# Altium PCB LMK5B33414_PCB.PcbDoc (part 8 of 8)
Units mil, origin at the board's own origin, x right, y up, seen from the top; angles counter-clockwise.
Board outline 7000 x 9161 mil, 8 copper layers (L1-Top Layer (GTL), L2-GND Plane (GP1), L3-Mid-Layer 2 (G1), L4-Mid-Layer 3 (G2), L5-Mid-Layer 4 (G3), L6-Mid-Layer 5 (G4), L7-Mid-Layer 6 (G5), L8-Bottom Layer (GBL)), stack 61.2 mil thick; 518 components, 286 nets, 1400 pads, 2231 vias.

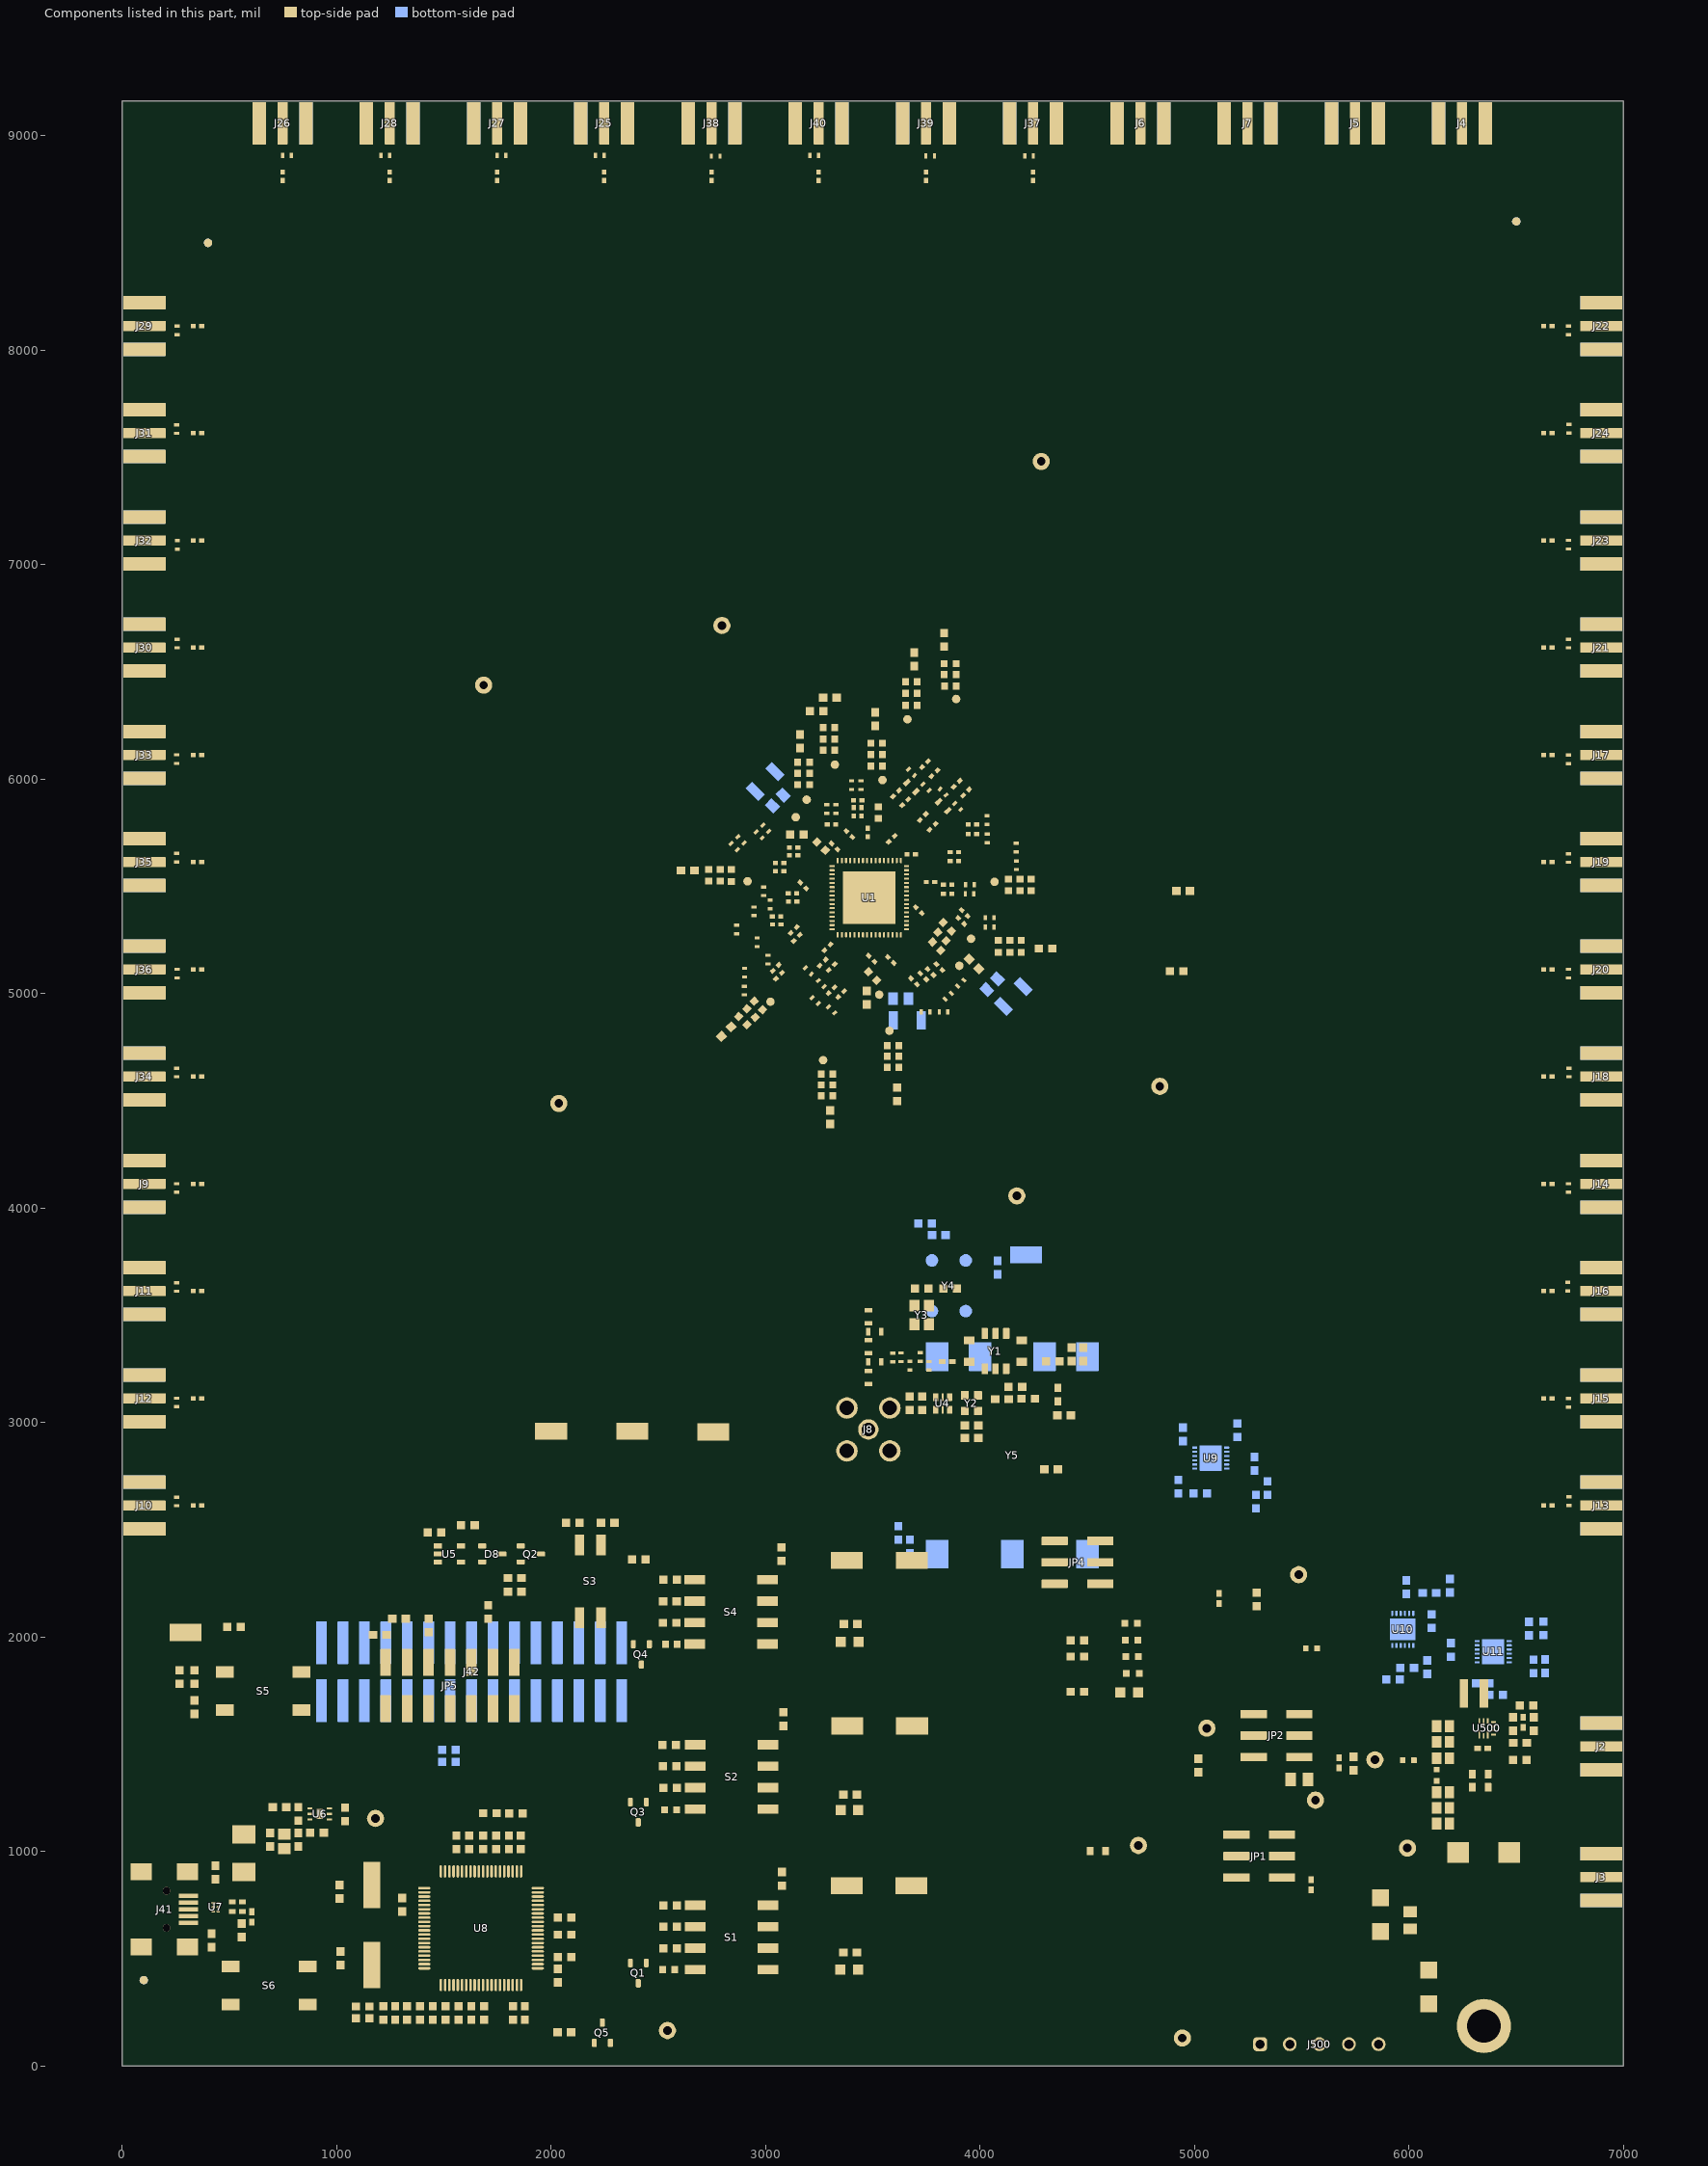
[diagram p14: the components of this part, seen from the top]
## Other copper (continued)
L2-GND Plane (GP1) (plane layer: these items are gaps in the copper):
  region: 3044.67,5727.19 3019.22,5752.65 2988.1,5721.54 3013.56,5696.08
  region: 2928.52,5672.34 2903.06,5697.8 2871.95,5666.68 2897.41,5641.23
  region: 4016.73,5353.67 3980.73,5353.67 3980.73,5309.67 4016.73,5309.67
  region: 3444.81,5909.83 3444.81,5945.83 3400.81,5945.83 3400.81,5909.83
  region: 3328.61,5797.65 3328.61,5833.65 3284.61,5833.65 3284.61,5797.65
  rectangle: 3885,5464 3921,5508
  pour cut-out: 3779.16,5891.79 3809.16,5921.79 3873.57,5857.38 3843.57,5827.38
  pour cut-out: 3631.8,5979.2 3661.8,6009.2 3726.2,5944.8 3696.2,5914.8
  pour cut-out: 3666.71,5927.74 3686.21,5908.24 3633.82,5855.85 3614.32,5875.35
  pour cut-out: 3624.01,5969.16 3643.51,5949.66 3591.12,5897.28 3571.62,5916.78
  pour cut-out: 3759.21,6105.24 3778.71,6085.74 3726.32,6033.35 3706.82,6052.85
  pour cut-out: 3803.21,6063.24 3822.71,6043.74 3770.32,5991.35 3750.82,6010.85
  pour cut-out: 3907.34,6014.08 3926.84,5994.58 3874.45,5942.19 3854.95,5961.69
  pour cut-out: 3950.79,5973.61 3970.29,5954.11 3917.9,5901.72 3898.4,5921.22
  pour cut-out: 3794.4,5813.9 3813.9,5794.4 3761.51,5742.01 3742.01,5761.51
  pour cut-out: 3749.04,5859.04 3768.54,5839.54 3716.15,5787.15 3696.65,5806.65
  pour cut-out: 391,8131.5 391,8095.5 312,8095.5 312,8131.5
  pour cut-out: 390,7632 390,7595 313,7595 313,7632
  pour cut-out: 390,7130.5 390,7095.5 312,7095.5 312,7130.5
  pour cut-out: 389,6632 389,6593 313,6593 313,6632
  pour cut-out: 389,6133 389,6093 313,6093 313,6133
  pour cut-out: 389,5632 389,5593 313,5593 313,5632
  pour cut-out: 389,5132 389,5093 313,5093 313,5132
  pour cut-out: 389,4632 389,4593 313,4593 313,4632
  pour cut-out: 389,4132 389,4093 313,4093 313,4132
  pour cut-out: 390.5,3632 390.5,3592 311.5,3592 311.5,3632
  pour cut-out: 389,3132 389,3093 313,3093 313,3132
  pour cut-out: 389,2632 389,2593 313,2593 313,2632
  pour cut-out: 6606,2593 6606,2632 6685,2632 6685,2593
  pour cut-out: 6607,3092 6607,3132 6685,3132 6685,3092
  pour cut-out: 6608,3593 6608,3633 6686,3633 6686,3593
  pour cut-out: 6608,4093 6608,4133 6686,4133 6686,4093
  pour cut-out: 6608.04,4592 6608.04,4633.5 6686,4633.5 6686,4592
  pour cut-out: 6608,5093 6608,5133 6685,5133 6685,5093
  pour cut-out: 6609,5591 6609,5633 6685,5633 6685,5591
  pour cut-out: 6608,6092 6608,6133 6685,6133 6685,6092
  pour cut-out: 6608,6592 6608,6632 6686,6632 6686,6592
  pour cut-out: 6606,7092 6606,7132 6686,7132 6686,7092
  pour cut-out: 6608,7593 6608,7632 6685,7632 6685,7593
  pour cut-out: 6609,8092 6609,8133 6685,8133 6685,8092
  pour cut-out: 4267,8772 4228,8772 4228,8848 4267,8848
  pour cut-out: 3768,8771 3727,8771 3727,8849 3768,8849
  pour cut-out: 3268,8771 3228,8771 3228,8848 3268,8848
  pour cut-out: 2768,8771 2728,8771 2728,8849 2768,8849
  pour cut-out: 2267,8771 2228,8771 2228,8848 2267,8848
  pour cut-out: 1768,8771 1727,8771 1727,8849 1768,8849
  pour cut-out: 1267,8771 1228,8771 1228,8848 1267,8848
  pour cut-out: 766,8770 729.5,8770 729.5,8848 766,8848
  pour cut-out: 153 vertices and 0 holes, not listed, extent -200,-200 7200,9361

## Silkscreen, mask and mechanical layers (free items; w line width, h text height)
Top Overlay:
  region: 3666,332.45 3666,426 3789,426 3789,332.45
  region: 3666,447 3666,546.55 3788,546.55 3788,447
  region: 3844.77,1188.55 3844.77,1428.55 4766.21,1428.55 4766.21,1188.55
  lines w10: 1185.7,1409.27 1197.7,1397.27 1349.7,1397.27 1361.7,1409.27 ; 1480.7,1413.27 1492.7,1401.27 1855.7,1401.27 1867.7,1413.27 ; 1961.4,1693.4 1976.4,1678.4 ; 1961.4,1853.4 1976.4,1868.4 ; 1976.4,1758.4 1976.4,1678.4 ; 1976.4,1788.4 1976.4,1868.4 ; 1991.4,1693.4 1976.4,1678.4 ; 1991.4,1853.4 1976.4,1868.4 ; 5454.2,2768.8 5454.2,2375.8 6037.8,2375.8 6037.8,1932
  text "Default DC  / coupled" at 243.7,3793.4 h72.83
  text "XO_P" at 3074.8,2938.87 h100
  text "GND" at 4248.6,2698.15 h55
  text "LDO3 INPUT" at 5068,2641.3 h55
  text "I2C Address" at 2059,2479 h65
  text "VIN3 DIRECT" at 4630.6,2475.9 h55
  text "Power DUT directly: / VIN1 (VDD) = 3.3 V (1 A) / VIN2 (VDDO) = 3.3 V (1 A) / VIN3 (XO_VDD) = 3.3 V (1A) / VIN4 not used." at 5468.5,2392.2 h80
  text "LDO to XO" at 4633.7,2389.9 h55
  text "GPIO2" at 2733.12,2365.21 h70
  text "DC/DC to XO" at 4636.2,2276.4 h55
  text "VDD" at 3105.27,2248.13 h65
  text "USB2ANY" at 3105.27,2150.6 h65
  text "GND" at 3105.27,2052.15 h65
  text "LED" at 3105.27,1953.13 h65
  text "Power DUT with DCDC: / VIN4 = 10 V to 15 V (1 A) / VIN1, VIN2, VIN3 not used. /  / Power DUT with LDO: / VIN1 = 3.6 V to 5 V (2 A) / VIN2, VIN3, VIN4 not used." at 6078.3,1914.7 h80
  text "DUT" at 2034.46,1786.11 h50 r90
  text "VIN2 DIRECT" at 5485,1673.4 h55
  text "MCU" at 2034.24,1671.11 h50 r90
  text "GPIO1" at 2748.52,1594.74 h70
  text "LDO to VDDO" at 5486.1,1570.3 h55
  text "DC/DC to VDDO" at 5490.6,1473.9 h55
  text "USER NOTE:" at 3838,1473 h100
  text "VDD" at 3105.27,1469.13 h65
  text "SDA" at 1242.7,1425.27 h65 r90
  text "SCL" at 1343.53,1425.27 h65 r90
  text "GND" at 1444.37,1425.27 h65 r90
  text "SCK" at 1545.2,1425.27 h65 r90
  text "MOSI" at 1646.03,1425.27 h65 r90
  text "MISO" at 1746.87,1425.27 h65 r90
  text "SCS" at 1847.7,1425.27 h65 r90
  text "USB2ANY" at 3105.27,1376.6 h65
  text "I2C" at 1235.7,1296.18 h100
  text "SPI" at 1640.7,1296.27 h100
  text "GND" at 3105.27,1278.15 h65
  text "LED" at 3105.27,1179.13 h65
  text "VIN1 DIRECT" at 5403.8,1106.2 h55
  text "LDO to VDD" at 5402.6,1005.4 h55
  text "DC/DC to VDD" at 5401.5,909.1 h55
  text "GPIO0" at 2760.92,845.74 h70
  text "VDD" at 3105.27,724.13 h65
  text "USB2ANY" at 3105.27,626.6 h65
  text "GND" at 3105.27,528.15 h65
  text "LED" at 3105.27,429.13 h65
  text "VIN4" at 5744.7,302 h75 r90
  text "VIN3" at 5610.5,300.3 h75 r90
  text "VIN1" at 5340.5,298.6 h75 r90
  text "VIN2" at 5478.1,298.6 h75 r90
  text "GND" at 5889.1,296.9 h75 r90
  text "PWR" at 4939.39,214.18 h100
  text ".Layer_Name" at 324,-1754 h100
Bottom Overlay:
  text ".Layer_Name" at 577,-1758.49 h50
Top Paste:
  text ".Layer_Name" at 577,-1758.49 h60
Bottom Paste:
  text ".Layer_Name" at 321,-1754.49 h60
Top Solder:
  circle w30: c3194,4708 r1
  circle w30: c3495,4839 r1
  circle w30: c4052,5003 r1
  circle w30: c4078,5447 r1
  circle w30: c3614,6032 r1
  circle w30: c3395,6066 r1
  circle w30: c3111,5924 r1
  circle w30: c3050,5854 r1
  circle w30: c2771,5690 r1
  circle w30: c2827,4962 r1
  circle w30: c3738,6246 r1
  circle w30: c3966,6408 r1
  circle w30: c4103,5394 r1
  circle w30: c4080,5121 r1
  text ".Layer_Name" at 577,-1758.49 h60
Bottom Solder:
  region: 3335,5300 3631,5300 3631,5593 3335,5593
  text ".Layer_Name" at 321,-1754.49 h60
Drill Guide:
  text ".Layer_Name" at 321,-1754.49 h60
  text ".Layer_Name" at 577,-1758.49 h60
M1 Board Outline:
  the board outline again, w5
  text ".Layer_Name" at 577,-1758.49 h60
M3 3D STEP Top:
  text ".Layer_Name" at 321,-1754.49 h60
  text ".Layer_Name" at 577,-1758.49 h60
M4 3D STEP Bottom:
  text ".Layer_Name" at 321,-1754.49 h60
  text ".Layer_Name" at 577,-1758.49 h60
M5 Assembly Top:
  lines w10: -292,-1830.17 6308,-1830.17 ; -292,-1626.83 6310,-1626.83 ; -292,-1423.5 -292,-2033.5 3713,-2033.5 6310,-2033.5 6310,-1423.5 -291.5,-1423.5 -291.5,-2033.5 1284,-2033.5 ; 2173,-2033.5 2173,-1423.5 ; 3440,-1626.83 3440,-1423.5 ; 4280,-1626.83 4280,-1423.5 ; 4902,-2040 4902,-1837.17
  text "COMPONENTS MARKED 'DNP' SHOULD NOT BE POPULATED." at 1403.5,-1188.5 h60
  text "ASSEMBLY VARIANT:" at 1403,-1304 h60
  text ".VariantName" at 2439,-1304 h60
  text "PCB VIEWED FROM TOP SIDE" at -228.5,-1555.67 h60
  text "BOARD #:" at 2248,-1555.67 h60
  text "REV:" at 3638,-1555.67 h60
  text ".PCB_Rev" at 3929.5,-1555.67 h60
  text "SVN REV:" at 4476,-1555.67 h60
  text ".VersionControl_RevNumber" at 4982,-1555.67 h60
  text "TID #:" at 2248,-1759 h60
  text ".TID" at 2793.5,-1759 h60
  text "PLOT NAME =" at -228.5,-1964.34 h60
  text ".plot_File_Name" at 577,-1964.34 h60
  text "GENERATED    :" at 2250,-1964.34 h60
  text ".Print_Date" at 3119.5,-1964.34 h60
  text ".Print_Time" at 3848.5,-1964.34 h60
M6 Assembly Bottom:
  lines w10: -292.5,-1627.33 6309.5,-1627.33 ; -290.5,-1830.67 6309.5,-1830.67 ; 1115.5,-2040.5 1115.5,-1837.67 ; 1737.5,-1627.33 1737.5,-1424 ; 2577.5,-1627.33 2577.5,-1424 ; 3844.5,-2034 3844.5,-1424 ; 4733.5,-2034 6309,-2034 6309,-1424 -292.5,-1424 -292.5,-2034 2304.5,-2034 6309.5,-2034 6309.5,-1424
  text "COMPONENTS MARKED 'DNP' SHOULD NOT BE POPULATED." at 6352,-1188 h60
  text ".VariantName" at 5308,-1304 h60
  text "ASSEMBLY VARIANT:" at 6347,-1304 h60
  text ".VersionControl_RevNumber" at 1035.5,-1556.17 h60
  text "SVN REV:" at 1541.5,-1556.17 h60
  text ".PCB_Rev" at 2088,-1556.17 h60
  text "REV:" at 2379.5,-1556.17 h60
  text "BOARD #:" at 3769.5,-1556.17 h60
  text "PCB VIEWED FROM BOTTOM SIDE" at 6246,-1556.17 h60
  text "IGNORE ->" at 2289.85,-1754.49 h60
  text ".TID" at 3224,-1759.5 h60
  text "TID #:" at 3769.5,-1759.5 h60
  text "TEXAS INSTRUMENTS" at 904.5,-1964.84 h60
  text ".Print_Time" at 2169,-1964.84 h60
  text ".Print_Date" at 2898,-1964.84 h60
  text "GENERATED    :" at 3767.5,-1964.84 h60
  text ".plot_File_Name" at 5440.5,-1964.84 h60
  text "PLOT NAME =" at 6246,-1964.84 h60
M7 LPKF Text Top:
  text ".Layer_Name" at 321,-1754.49 h60
M9 Title Sheet:
  lines w10: -765,-2515.61 -765,12484.39 19235,12484.39 19235,-2515.61 ; -765,1234.39 -465,1234.39 ; -765,4984.39 -465,4984.39 ; -765,8734.39 -465,8734.39 ; -665,-2615.61 19335,-2615.61 ; 2570,-2515.61 2570,-2215.61 ; 2570,12184.39 2570,12484.39 ; 5900,-2515.61 5900,-2215.61 ; 5900,12184.39 5900,12484.39 ; 9235,-2515.61 9235,-2215.61 ; 9235,12184.39 9235,12484.39 ; 10948.5,-2224.61 10948.5,-1614.61 15931,-1614.61 ; 12565,-2515.61 12565,-2215.61 ; 12565,12184.39 12565,12484.39 ; 15900,-2515.61 15900,-2215.61 ; 15900,12184.39 15900,12484.39 ; 15931,-2224.61 15931,-1614.61 ; 15931,-1914.61 18931,-1914.61 ; 15931,-1314.61 18931,-1314.61 ; 15932,-720.61 18932,-720.61 ; 17436,-2214.61 17436,-1614.61 ; 18931,-1614.61 15931,-1614.61 ; 18931,-1014.61 15931,-1014.61 ; 18935,1234.39 19235,1234.39 ; 18935,4984.39 19235,4984.39 ; 18935,8734.39 19235,8734.39 ; 18936,-220.11 15932,-220.11 15931,-220.11 15931,-720.61 15931,-1014.61 ; 15931,-1614.61 15931,-1014.61 ; -465,-2215.61 18935,-2215.61 18935,12184.39 -465,12184.39 -465,-2215.61
  text "1" at 886.34,12299.39 h70
  text "2" at 4212,12299.39 h70
  text "3" at 7542,12299.39 h70
  text "4" at 10877,12299.39 h70
  text "5" at 14202,12299.39 h70
  text "6" at 17537,12299.39 h70
  text "A" at -635,10521.39 h70
  text "A" at 19065,10521.39 h70
  text "B" at -635,6771.39 h70
  text "B" at 19065,6771.39 h70
  text "C" at -635,3021.39 h70
  text "C" at 19065,3021.39 h70
  text "D" at -635,-728.61 h70
  text "D" at 19065,-728.61 h70
  text "PROJECT TITLE:" at 15971,-813.61 h45
  text "DESIGNED FOR:" at 15971,-1114.61 h45
  text ".PRJ_Customer" at 16021,-1254.61 h70
  text "FILE NAME:" at 15971,-1414.61 h45
  text "Texas Instruments (TI) and/or its licensors do not warrant the accuracy or completeness of this specification" at 11001.5,-1696.45 h45
  text "ENGINEER:" at 15971,-1704.61 h45
  text "LAYOUT BY:" at 17476,-1704.61 h45
  text ".Layer_Name" at 415,-1755 h60
  text "or any information contained therein. TI and/or its licensors do not warrant that this design will meet" at 10956.51,-1809.11 h45
  text "the specifications, will be suitable for your application or fit for any particular purpose, or will operate in" at 10956.51,-1921.78 h45
  text "ALTIUM DESIGNER VERSION:" at 17476,-2014.61 h45
  text "an implementation. TI and/or its licensors do not warrant that the design is production worthy. You should" at 10956.51,-2034.44 h45
  text "completely validate and test your design implementation to confirm the system functionality for your application." at 11001.5,-2147.11 h45
  text ".print_Scale" at 16021,-2147.94 h70
  text ".Application_BuildNumber" at 17526.5,-2147.94 h70
  text "1" at 886.34,-2400.61 h70
  text "2" at 4212,-2400.61 h70
  text "3" at 7542,-2400.61 h70
  text "4" at 10877,-2400.61 h70
  text "5" at 14202,-2400.61 h70
  text "6" at 17537,-2400.61 h70
M10 Fab Notes:
  drawing of 203 lines, arcs and shapes, not listed
  text "C" at 16536.76,6898.2 h137.54
  text "o" at 16602.93,6898.2 h137.54
  text "n" at 16669.1,6898.2 h137.54
  text "t" at 16735.27,6898.2 h137.54
  text "r" at 16782.53,6898.2 h137.54
  text "o" at 16829.8,6898.2 h137.54
  text "l" at 16895.97,6898.2 h137.54
  text "l" at 16924.33,6898.2 h137.54
  text "e" at 16952.69,6898.2 h137.54
  text "d" at 17018.86,6898.2 h137.54
  text "I" at 17113.39,6898.2 h137.54
  text "m" at 17141.75,6898.2 h137.54
  text "p" at 17245.73,6898.2 h137.54
  text "e" at 17311.9,6898.2 h137.54
  text "d" at 17378.08,6898.2 h137.54
  text "a" at 17444.25,6898.2 h137.54
  text "n" at 17500.96,6898.2 h137.54
  text "c" at 17567.14,6898.2 h137.54
  text "e" at 17614.4,6898.2 h137.54
  text "L" at 15192.16,6690.23 h137.54
  text "a" at 15248.88,6690.23 h137.54
  text "y" at 15305.6,6690.23 h137.54
  text "e" at 15362.31,6690.23 h137.54
  text "r" at 15428.48,6690.23 h137.54
  text "S" at 15741.36,6690.23 h137.54
  text "i" at 15798.08,6690.23 h137.54
  text "n" at 15826.44,6690.23 h137.54
  text "g" at 15892.61,6690.23 h137.54
  text "l" at 15949.33,6690.23 h137.54
  text "e" at 15977.69,6690.23 h137.54
  text "-" at 16043.86,6690.23 h137.54
  text "E" at 16081.67,6690.23 h137.54
  text "n" at 16138.39,6690.23 h137.54
  text "d" at 16204.56,6690.23 h137.54
  text "e" at 16270.73,6690.23 h137.54
  text "d" at 16336.9,6690.23 h137.54
  text "Ω" at 16726.14,6690.23 h137.54
  text "+" at 17085.96,6690.23 h137.54
  text "/" at 17142.68,6690.23 h137.54
  text "-" at 17199.39,6690.23 h137.54
  text "%" at 17265.57,6690.23 h137.54
  text "R" at 17587.81,6690.23 h137.54
  text "e" at 17653.99,6690.23 h137.54
  text "f" at 17720.16,6690.23 h137.54
  text "e" at 17757.97,6690.23 h137.54
  text "r" at 17824.14,6690.23 h137.54
  text "e" at 17871.41,6690.23 h137.54
  text "n" at 17937.58,6690.23 h137.54
  text "c" at 18003.75,6690.23 h137.54
  text "e" at 18051.01,6690.23 h137.54
  text "L" at 18145.54,6690.23 h137.54
  text "a" at 18202.26,6690.23 h137.54
  text "y" at 18258.98,6690.23 h137.54
  text "e" at 18315.7,6690.23 h137.54
  text "r" at 18381.87,6690.23 h137.54
  text "s" at 18429.13,6690.23 h137.54
  text "L1" at 15303.79,6496.3 h137.54
  text "1" at 15881.4,6496.3 h137.54
  text "1" at 15947.57,6496.3 h137.54
  text "m" at 16013.74,6496.3 h137.54
  text "i" at 16108.27,6496.3 h137.54
  text "l" at 16146.08,6496.3 h137.54
  text "s" at 16183.89,6496.3 h137.54
  text "5" at 16705.2,6496.3 h137.54
  text "0" at 16771.37,6496.3 h137.54
  text "1" at 17150.24,6496.3 h137.54
  text "0" at 17216.41,6496.3 h137.54
  text "L2 (GP1)" at 17992.98,6496.3 h137.54
  text "100" at 16708.41,6293 h137.54
  text "1" at 17149.45,6293 h137.54
  text "0" at 17215.63,6293 h137.54
  text "L1" at 15297.79,6291.3 h137.54
  text "L2 (GP1)" at 17979.19,6280 h137.54
  text "Diff 100 ohms / 8 mil wide, 8 mil space" at 15730,6245 h100
  text "5" at 16698.41,6093 h137.54
  text "0" at 16764.58,6093 h137.54
  text "1" at 17149.45,6093 h137.54
  text "0" at 17215.63,6093 h137.54
  text "5" at 15900.78,6092 h137.54
  text "m" at 15966.95,6092 h137.54
  text "i" at 16061.48,6092 h137.54
  text "l" at 16099.29,6092 h137.54
  text "s" at 16137.11,6092 h137.54
  text "L5 and L7" at 17969.19,6080 h137.54
  text "L6" at 15285,6078 h137.54
  text "5" at 16694.22,5861 h137.54
  text "0" at 16760.39,5861 h137.54
  text "1" at 17145.26,5861 h137.54
  text "0" at 17211.43,5861 h137.54
  text "11" at 15896.59,5860 h137.54
  text "m" at 16022.76,5860 h137.54
  text "i" at 16117.29,5860 h137.54
  text "l" at 16155.1,5860 h137.54
  text "s" at 16192.91,5860 h137.54
  text "L7" at 17965,5848 h137.54
  text "L8" at 15280.81,5846 h137.54
  text "DESIGN INFORMATION" at 16758.02,5364 h60
  text "MIN. TRACK WIDTH:" at 16113.46,5184 h60
  text "5" at 17209.7,5184 h60
  text "MIL" at 17364.46,5184 h60
  text "MIN. CLEARANCE:" at 16113.46,5052 h60
  text "5" at 17149.7,5052 h60
  text "MIL" at 17364.46,5052 h60
  text "MIN. VIA PAD SIZE:" at 16113.46,4920 h60
  text "19.7" at 17130,4920 h60
  text "MIL" at 17364.46,4920 h60
  text "0.05mm (2MIL)" at 16808.46,4778.29 h60
  text "MINIMUM ANNULAR RING" at 15784.23,4774 h60
  text "EXTERNAL" at 17516.46,4774 h60
  text "PER" at 15984.23,4656 h60
  text "IPC-D-275 CLASS 2 LEVEL C" at 16204.23,4656 h60
  text "MIL, HOLES" at 17692.46,4543.71 h60
  text "+/-" at 17300,4543 h60
  text "+/-" at 18154,4543 h60
  text "REGISTRATION TOLERANCES:" at 15784.23,4538 h60
  text "METAL" at 16984,4538 h60
  text "5" at 17560.2,4538 h60
  text "3" at 18393.2,4538 h60
  text "MIL" at 18509.46,4538 h60
  text "+/-" at 18154,4425 h60
  text "HOLE SIZE TOLERANCE (UNLESS OTHERWISE SPECIFIED):" at 15784.23,4420 h60
  text "3" at 18393.2,4420 h60
  text "MIL" at 18509.46,4420 h60
  text "MATERIAL:" at 15709.46,4210.54 h60
  text "FR-4 High Tg" at 16695.9,4070.21 h60
  text "FR-408" at 16130.46,4061.64 h60
  text "OTHER" at 17618.46,4061.64 h60
  text "X" at 16541,4058 h60
  text "62 MIL (1.6mm) +/-10%" at 16450.56,3898.92 h60
  text "THICKNESS:" at 15784.23,3894.64 h60
  text "X" at 16322.4,3894.64 h60
  text "OTHER" at 17735.46,3894.64 h60
  text "TOLERANCE:" at 15784.23,3736.64 h60
  text "X" at 16623.53,3736.64 h60
  text "ANSI IPC-6012 TYPE 3 CLASS 2" at 16810.48,3736.64 h60
  text "OTHER +/-" at 16810.46,3580.64 h60
  text "BOW & TWIST:" at 15784.23,3423.64 h60
  text "X" at 16623.53,3423.64 h60
  text "ANSI IPC-6012 TYPE 3 CLASS 2" at 16810.48,3423.64 h60
  text "OTHER +/-" at 16810.46,3265.13 h60
  text "DRILLING:" at 15709.46,3126.64 h60
  text "REFERENCE:" at 15784.23,3009.64 h60
  text "X" at 16432.46,3009.64 h60
  text "AS SHOWN" at 16619.46,3009.64 h60
  text "X" at 17333.46,3009.64 h60
  text "NC_DRILL FILES" at 17470.46,3009.64 h60
  text "PTH COPPER THICKNESS:" at 15784.23,2851.64 h60
  text "X" at 16914.46,2851.64 h60
  text "20-30 um" at 17051.46,2851.64 h60
  text "OTHER" at 17768.46,2851.64 h60
  text "BOARD FINISH:" at 15709.46,2692.64 h60
  text "SILKSCREEN:" at 15864.68,2574.64 h60
  text "X" at 16813.46,2574.64 h60
  text "TOP" at 16939.46,2574.64 h60
  text "X" at 17323.46,2574.64 h60
  text "BOTTOM" at 17450.46,2574.64 h60
  text "SILKSCREEN COLOR:" at 15864.68,2407.64 h60
  text "X" at 16812.42,2407.64 h60
  text "WHITE" at 16939.46,2407.64 h60
  text "OTHER" at 17450.46,2407.64 h60
  text "X" at 16943.42,2248.44 h60
  text "GREEN" at 17070.46,2248.44 h60
  text "OTHER" at 17688.46,2248.44 h60
  text "SOLDER RESIST COLOR:" at 15864.68,2237.64 h60
  text "X" at 16943.42,2078.44 h60
  text "MATTE" at 17070.46,2078.44 h60
  text "SEMI-GLOSS" at 17688,2077.8 h60
  text "IMMERSION GOLD (ENIG)" at 16770.46,1889.92 h60
  text "ENEPIG" at 18108,1886.64 h60
  text "SURFACE FINISH:" at 15709.46,1885.64 h60
  text "X" at 16583.51,1885.64 h60
  text "IMM. TIN/SILVER OR EQUIV" at 16039,1728.64 h60
  text "OTHER" at 17470.46,1728.64 h60
  text "ARRAY/PANEL:" at 15709.46,1549.64 h60
  text "CUT AND TRIM PER M1 BOARD OUTLINE" at 16770.46,1545.35 h60
  text "N.C. ROUTE" at 16770.46,1393.64 h60
  text "V. SCORE" at 17636.46,1393.64 h60
  text "X" at 16585,1383 h60
  text "CERTIFICATION:" at 15709.46,1256.64 h60
  text "MATERIALS AND WORKMANSHIP FOR ALL PCBS" at 16434.46,1256.64 h60
  text "TO MEET OR EXCEED THE REQUIREMENTS OF:" at 16434.46,1158.64 h60
  text "X" at 16060.96,1022.13 h60
  text "ANSI IPC-A-600F CLASS ->" at 16199.96,1022.13 h60
  text "X" at 17839.02,1022.13 h60
  text "2" at 17957.96,1022.14 h60
  text "1" at 17642.96,1020.64 h60
  text "3" at 18311.96,1020.64 h60
  text "X" at 16875.02,862.64 h60
  text "RoHS" at 17011.96,862.64 h60
  text "OTHER" at 17656.36,862.64 h60
  text "PER ORDER" at 18053.42,862.64 h60
  text "ALL BOARDS MUST MEET OR EXCEED UL94-V0 REQUIREMENTS." at 15737,697 h60
  text "PCB MUST BEAR THE UL94V-0 UL REGISTERED MATERIAL ID NUMBER" at 15737,577 h60
  text "ADDITIONAL REQUIREMENTS:" at 15709.46,403.64 h60
  text "MICROSECTION:" at 15784.23,288.64 h60
  text "YES" at 16689.96,288.64 h60
  text "REQUIRED" at 17551.46,132.49 h60
  text "BARE BOARD ELEC. TEST:" at 15784.23,129.64 h60
  text "NONE" at 17089.96,129.64 h60
  text "X" at 17424.46,129.64 h60
  text "PER ORDER" at 18143.46,129.64 h60
  text ".Layer_Name" at 321,-1754.49 h60
M11 Gerber Information:
  lines w10: -292,-1830.17 6308,-1830.17 ; -292,-1626.83 6310,-1626.83 ; -292,-1423.5 -292,-2033.5 3713,-2033.5 6310,-2033.5 6310,-1423.5 -291.5,-1423.5 -291.5,-2033.5 1284,-2033.5 ; 2173,-2033.5 2173,-1423.5 ; 3440,-1626.83 3440,-1423.5 ; 4280,-1626.83 4280,-1423.5 ; 4902,-2040 4902,-1837.17
  text "ALL ARTWORK VIEWED FROM TOP SIDE" at -228.5,-1555.67 h60
  text "BOARD #:" at 2248,-1555.67 h60
  text "REV:" at 3638,-1555.67 h60
  text ".PCB_Rev" at 3929.5,-1555.67 h60
  text "SVN REV:" at 4476,-1555.67 h60
  text ".VersionControl_RevNumber" at 4982,-1555.67 h60
  text "LAYER NAME =" at -228.5,-1758.49 h60
  text "TID #:" at 2248,-1759 h60
  text ".TID" at 2793.5,-1759 h60
  text "PLOT NAME =" at -228.5,-1964.34 h60
  text ".plot_File_Name" at 577,-1964.34 h60
  text "GENERATED    :" at 2250,-1964.34 h60
  text ".Print_Date" at 3119.5,-1964.34 h60
  text ".Print_Time" at 3848.5,-1964.34 h60
M12 Stackup:
  drawing of 503 lines, arcs and shapes, not listed
  text "Layer" at 13908.47,11611 h60
  text "Name" at 14318.38,11611 h60
  text "Material" at 15648,11611 h60
  text "Thickness" at 16507.77,11611 h60
  text "Constant" at 17157.6,11611 h60
  text "Board Layer Stack" at 17727.46,11611 h60
  text "1" at 13908.47,11491 h60
  text "Top Overlay" at 14318.38,11491 h60
  text "2" at 13908.47,11371 h60
  text "Top Solder" at 14318.38,11371 h60
  text "Solder Resist" at 15648,11371 h60
  text "0.40mil" at 16507.77,11371 h60
  text "3.5" at 17157.6,11371 h60
  text "3" at 13908.47,11251 h60
  text "L1-Top Layer (GTL)" at 14318.38,11251 h60
  text "Copper" at 15648,11251 h60
  text "1.40mil" at 16507.77,11251 h60
  text "4" at 13908.47,11131 h60
  text "Dielectric1" at 14318.38,11131 h60
  text "FR-4" at 15648,11131 h60
  text "7.00mil" at 16507.77,11131 h60
  text "4.6" at 17157.6,11131 h60
  text "5" at 13908.47,11011 h60
  text "L2-GND Plane (GP1)" at 14318.38,11011 h60
  text "Copper" at 15648,11011 h60
  text "1.40mil" at 16507.77,11011 h60
  text "6" at 13908.47,10891 h60
  text "Dielectric2" at 14318.38,10891 h60
  text "FR-4" at 15648,10891 h60
  text "7.00mil" at 16507.77,10891 h60
  text "4.6" at 17157.6,10891 h60
  text "7" at 13908.47,10771 h60
  text "L3-Mid-Layer 2 (G1)" at 14318.38,10771 h60
  text "Copper" at 15648,10771 h60
  text "1.40mil" at 16507.77,10771 h60
  text "8" at 13908.47,10651 h60
  text "Dielectric3" at 14318.38,10651 h60
  text "FR-4" at 15648,10651 h60
  text "5.00mil" at 16507.77,10651 h60
  text "4.6" at 17157.6,10651 h60
  text "9" at 13908.47,10531 h60
  text "L4-Mid-Layer 3 (G2)" at 14318.38,10531 h60
  text "Copper" at 15648,10531 h60
  text "1.40mil" at 16507.77,10531 h60
  text "10" at 13908.47,10411 h60
  text "Dielectric4" at 14318.38,10411 h60
  text "FR-4" at 15648,10411 h60
  text "12.00mil" at 16507.77,10411 h60
  text "4.6" at 17157.6,10411 h60
  text "11" at 13908.47,10291 h60
  text "L5-Mid-Layer 4 (G3)" at 14318.38,10291 h60
  text "Copper" at 15648,10291 h60
  text "1.40mil" at 16507.77,10291 h60
  text "12" at 13908.47,10171 h60
  text "Dielectric5" at 14318.38,10171 h60
  text "FR-4" at 15648,10171 h60
  text "5.00mil" at 16507.77,10171 h60
  text "4.6" at 17157.6,10171 h60
  text "13" at 13908.47,10051 h60
  text "L6-Mid-Layer 5 (G4)" at 14318.38,10051 h60
  text "Copper" at 15648,10051 h60
  text "1.40mil" at 16507.77,10051 h60
  text "14" at 13908.47,9931 h60
  text "Dielectric6" at 14318.38,9931 h60
  text "FR-4" at 15648,9931 h60
  text "7.00mil" at 16507.77,9931 h60
  text "4.6" at 17157.6,9931 h60
  text "15" at 13908.47,9811 h60
  text "L7-Mid-Layer 6 (G5)" at 14318.38,9811 h60
  text "Copper" at 15648,9811 h60
  text "1.40mil" at 16507.77,9811 h60
  text "16" at 13908.47,9691 h60
  text "Dielectric7" at 14318.38,9691 h60
  text "FR-4" at 15648,9691 h60
  text "7.00mil" at 16507.77,9691 h60
  text "4.6" at 17157.6,9691 h60
  text "17" at 13908.47,9571 h60
  text "L8-Bottom Layer (GBL)" at 14318.38,9571 h60
  text "Copper" at 15648,9571 h60
  text "1.40mil" at 16507.77,9571 h60
  text "18" at 13908.47,9451 h60
  text "Bottom Solder" at 14318.38,9451 h60
  text "Solder Resist" at 15648,9451 h60
  text "0.40mil" at 16507.77,9451 h60
  text "3.5" at 17157.6,9451 h60
  text "19" at 13908.47,9331 h60
  text "Bottom Overlay" at 14318.38,9331 h60
  text ".Layer_Name" at 321,-1754.49 h60
M13 Component Bodies Top:
  text ".Layer_Name" at 321,-1754.49 h60
  text ".Layer_Name" at 577,-1758.49 h60
M14 Component Bodies Bottom:
  text ".Layer_Name" at 321,-1754.49 h60
  text ".Layer_Name" at 577,-1758.49 h60
M15 Courtyards Top:
  text ".Layer_Name" at 321,-1754.49 h60
  text ".Layer_Name" at 577,-1758.49 h60
M16 Courtyards Bottom:
  text ".Layer_Name" at 321,-1754.49 h60
  text ".Layer_Name" at 577,-1758.49 h60
Drill Drawing:
  lines w10: 7604.09,10246 7604.09,10262.67 7620.76,10279.33 7604.09,10296 7604.09,10312.67 7620.76,10312.67 7637.43,10296 7654.09,10312.67 7670.76,10312.67 7670.76,10296 7654.09,10279.33 7670.76,10262.67 7670.76,10246 7654.09,10246 7637.43,10262.67 7620.76,10246 7604.09,10246 ; 7604.09,10396 7637.43,10412.67 7670.76,10396 7654.09,10429.33 7670.76,10462.67 7637.43,10446 7604.09,10462.67 7620.76,10429.33 7604.09,10396 ; 7604.09,10546 7670.76,10546 7670.76,10612.67 7604.09,10612.67 7604.09,10546 ; 7604.09,10712.67 7620.76,10712.67 7620.76,10696 7654.09,10696 7654.09,10712.67 7670.76,10712.67 7670.76,10746 7654.09,10746 7654.09,10762.67 7620.76,10762.67 7620.76,10746 7604.09,10746 7604.09,10712.67 ; 7604.09,10879.33 7637.43,10846 7670.76,10879.33 7637.43,10912.67 7604.09,10879.33 ; 7604.09,11012.67 7620.76,11012.67 7637.43,10996 7654.09,11012.67 7670.76,11012.67 7654.09,11029.33 7670.76,11046 7654.09,11046 7637.43,11062.67 7620.76,11046 7604.09,11046 7620.76,11029.33 7604.09,11012.67 ; 7604.09,11362.67 7670.76,11362.67 7637.43,11296 7604.09,11362.67 ; 7604.09,11446 7604.09,11462.67 7620.76,11479.33 7604.09,11496 7604.09,11512.67 7620.76,11512.67 7637.43,11496 7654.09,11512.67 7670.76,11512.67 7670.76,11496 7654.09,11479.33 7670.76,11462.67 7670.76,11446 7654.09,11446 7637.43,11462.67 7620.76,11446 7604.09,11446 ; 7617.43,10259.33 7617.43,10269.33 7627.43,10279.33 7617.43,10289.33 7617.43,10299.33 7627.43,10299.33 7637.43,10289.33 7647.43,10299.33 7657.43,10299.33 7657.43,10289.33 7647.43,10279.33 7657.43,10269.33 7657.43,10259.33 7647.43,10259.33 7637.43,10269.33 7627.43,10259.33 7617.43,10259.33 ; 7617.43,10409.33 7637.43,10419.33 7657.43,10409.33 7647.43,10429.33 7657.43,10449.33 7637.43,10439.33 7617.43,10449.33 7627.43,10429.33 7617.43,10409.33
  lines w15: 7544.3,10051 13708.56,10051 ; 7544.3,11551 13708.56,11551 ; 8095.18,9901 8095.18,11701 ; 8745,9901 8745,11701 ; 9894.67,9901 9894.67,11701 ; 10400.54,9901 10400.54,11701 ; 11134.34,9901 11134.34,11701 ; 7544.3,9901 13708.56,9901 13708.56,11701 7544.3,11701 7544.3,9901
  text "Symbol" at 7634.3,11596 h72
  text "Count" at 8140.18,11596 h72
  text "Hole Size" at 8790,11596 h72
  text "Plated" at 9939.67,11596 h72
  text "Hole Type" at 10445.54,11596 h72
  text "Drill Layer Pair" at 11179.34,11596 h72
  text "1" at 8140.18,11446 h60
  text "62.00mil (1.575mm)" at 8790,11446 h60
  text "PTH" at 9939.67,11446 h60
  text "Round" at 10445.54,11446 h60
  text "L1-Top Layer (GTL) - L8-Bottom Layer (GBL)" at 11179.34,11446 h60
  text "1" at 8140.18,11296 h60
  text "157.00mil (3.988mm)" at 8790,11296 h60
  text "PTH" at 9939.67,11296 h60
  text "Round" at 10445.54,11296 h60
  text "L1-Top Layer (GTL) - L8-Bottom Layer (GBL)" at 11179.34,11296 h60
  text "2" at 8140.18,11146 h60
  text "35.43mil (0.900mm)" at 8790,11146 h60
  text "NPTH" at 9939.67,11146 h60
  text "Round" at 10445.54,11146 h60
  text "L1-Top Layer (GTL) - L8-Bottom Layer (GBL)" at 11179.34,11146 h60
  text "B" at 7605.21,11136.01 h66.67
  text "4" at 8140.18,10996 h60
  text "52.00mil (1.321mm)" at 8790,10996 h60
  text "PTH" at 9939.67,10996 h60
  text "Round" at 10445.54,10996 h60
  text "L1-Top Layer (GTL) - L8-Bottom Layer (GBL)" at 11179.34,10996 h60
  text "4" at 8140.18,10846 h60
  text "67.00mil (1.702mm)" at 8790,10846 h60
  text "PTH" at 9939.67,10846 h60
  text "Round" at 10445.54,10846 h60
  text "L1-Top Layer (GTL) - L8-Bottom Layer (GBL)" at 11179.34,10846 h60
  text "6" at 8140.18,10696 h60
  text "19.69mil (0.500mm)" at 8790,10696 h60
  text "PTH" at 9939.67,10696 h60
  text "Round" at 10445.54,10696 h60
  text "L1-Top Layer (GTL) - L8-Bottom Layer (GBL)" at 11179.34,10696 h60
  text "16" at 8140.18,10546 h60
  text "40.00mil (1.016mm)" at 8790,10546 h60
  text "PTH" at 9939.67,10546 h60
  text "Round" at 10445.54,10546 h60
  text "L1-Top Layer (GTL) - L8-Bottom Layer (GBL)" at 11179.34,10546 h60
  text "56" at 8140.18,10396 h60
  text "7.87mil (0.200mm)" at 8790,10396 h60
  text "PTH" at 9939.67,10396 h60
  text "Round" at 10445.54,10396 h60
  text "L1-Top Layer (GTL) - L8-Bottom Layer (GBL)" at 11179.34,10396 h60
  text "780" at 8140.18,10246 h60
  text "12.00mil (0.305mm)" at 8790,10246 h60
  text "PTH" at 9939.67,10246 h60
  text "Round" at 10445.54,10246 h60
  text "L1-Top Layer (GTL) - L8-Bottom Layer (GBL)" at 11179.34,10246 h60
  text "1445" at 8140.18,10096 h60
  text "10.00mil (0.254mm)" at 8790,10096 h60
  text "PTH" at 9939.67,10096 h60
  text "Round" at 10445.54,10096 h60
  text "L1-Top Layer (GTL) - L8-Bottom Layer (GBL)" at 11179.34,10096 h60
  text "C" at 7605.21,10086.01 h66.67
  text "2315 Total" at 8140.18,9946 h60
  text ".Layer_Name" at 321,-1754.49 h60
M18 Embedded Assembly:
  text ".Layer_Name" at 577,-1758.49 h60

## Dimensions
7000,9161 to 7000,0 on M2 Board Dimensions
